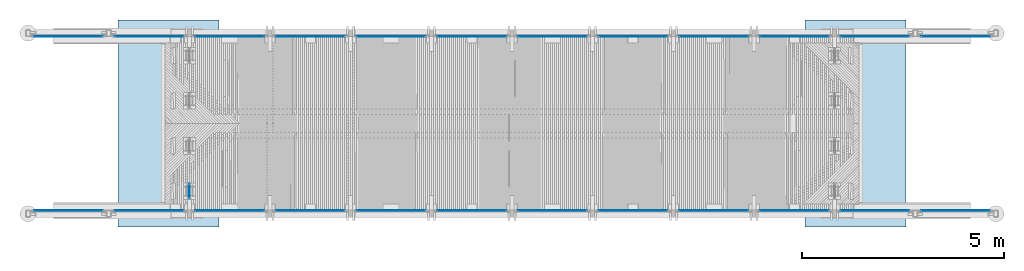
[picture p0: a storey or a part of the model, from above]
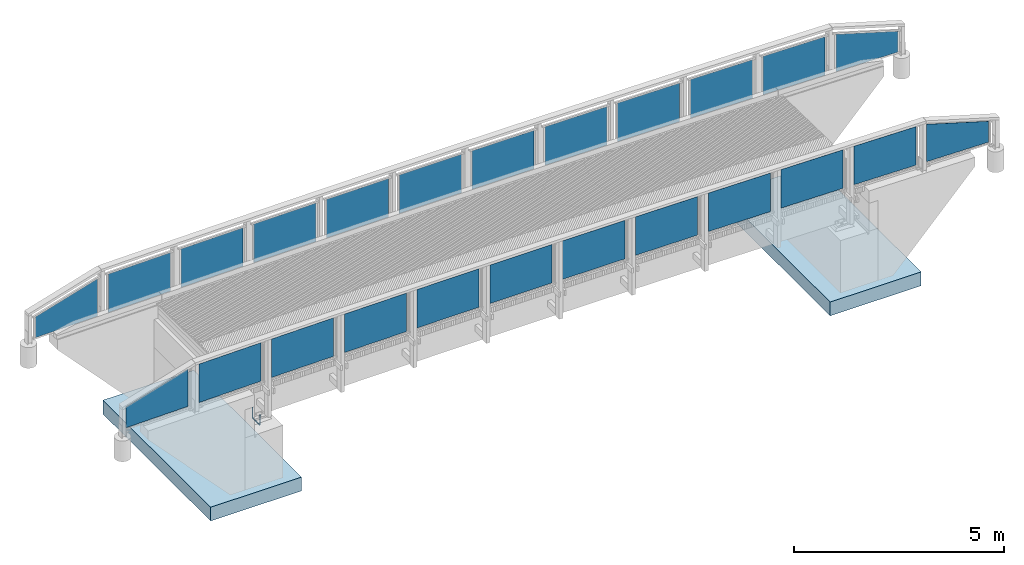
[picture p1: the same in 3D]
Properties of the parts of a building model (IFC2X3), part 2 of 2

# IfcBeam: 50*50 (546)
Name | Bottom elevation | Top elevation | Weight (kg) | Area per tons (m2) | Net surface area (m2) | Height (mm) | Tekla Quantity, Length (mm) | BaseQuantities, Length (mm) | OuterSurfaceArea (m2) | NetVolume (m3) | NetWeight (kg)
BEAM | +3.146 | +3.252 | 4.1 | 135.1 | 0.6 | 50 | 2880.8 | 2880.77 | 0.572949 | 0.0070735 | 4.2441
BEAM | +3.146 | +3.252 | 4.1 | 135.1 | 0.6 | 50 | 2880.8 | 2880.76 | 0.572941 | 0.00707335 | 4.24401
BEAM | +3.146 | +3.251 | 4.1 | 135.1 | 0.6 | 50 | 2880.8 | 2880.77 | 0.572949 | 0.0070735 | 4.2441
BEAM | +3.146 | +3.251 | 4.1 | 135.1 | 0.6 | 50 | 2880.8 | 2880.76 | 0.572941 | 0.00707335 | 4.24401
BEAM | +3.145 | +3.251 | 4.1 | 135.1 | 0.6 | 50 | 2880.8 | 2880.77 | 0.572949 | 0.0070735 | 4.2441
BEAM | +3.145 | +3.251 | 4.1 | 135.1 | 0.6 | 50 | 2880.8 | 2880.76 | 0.572941 | 0.00707335 | 4.24401
BEAM | +3.144 | +3.251 | 4.1 | 135.1 | 0.6 | 50 | 2880.8 | 2880.77 | 0.572949 | 0.0070735 | 4.2441
BEAM | +3.144 | +3.251 | 4.1 | 135.1 | 0.6 | 50 | 2880.8 | 2880.76 | 0.572941 | 0.00707335 | 4.24401
BEAM | +3.144 | +3.250 | 4.1 | 135.1 | 0.6 | 50 | 2880.8 | 2880.77 | 0.572949 | 0.0070735 | 4.2441
BEAM | +3.144 | +3.250 | 4.1 | 135.1 | 0.6 | 50 | 2880.8 | 2880.76 | 0.572941 | 0.00707335 | 4.24401
BEAM | +3.143 | +3.250 | 4.1 | 135.1 | 0.6 | 50 | 2880.8 | 2880.77 | 0.572949 | 0.0070735 | 4.2441
BEAM | +3.143 | +3.250 | 4.1 | 135.1 | 0.6 | 50 | 2880.8 | 2880.76 | 0.572941 | 0.00707335 | 4.24401
2 x BEAM | +3.142 | +3.249 | 4.1 | 135.1 | 0.6 | 50 | 2880.8 | 2880.77 | 0.572949 | 0.0070735 | 4.2441
2 x BEAM | +3.142 | +3.249 | 4.1 | 135.1 | 0.6 | 50 | 2880.8 | 2880.76 | 0.572941 | 0.00707335 | 4.24401
BEAM | +3.141 | +3.248 | 4.1 | 135.1 | 0.6 | 50 | 2880.8 | 2880.77 | 0.572949 | 0.0070735 | 4.2441
BEAM | +3.141 | +3.248 | 4.1 | 135.1 | 0.6 | 50 | 2880.8 | 2880.76 | 0.572941 | 0.00707335 | 4.24401
BEAM | +3.140 | +3.248 | 4.1 | 135.1 | 0.6 | 50 | 2880.8 | 2880.77 | 0.572949 | 0.0070735 | 4.2441
BEAM | +3.140 | +3.248 | 4.1 | 135.1 | 0.6 | 50 | 2880.8 | 2880.76 | 0.572941 | 0.00707335 | 4.24401
BEAM | +3.140 | +3.247 | 4.1 | 135.1 | 0.6 | 50 | 2880.8 | 2880.77 | 0.572949 | 0.0070735 | 4.2441
BEAM | +3.140 | +3.247 | 4.1 | 135.1 | 0.6 | 50 | 2880.8 | 2880.76 | 0.572941 | 0.00707335 | 4.24401
BEAM | +3.139 | +3.247 | 4.1 | 135.1 | 0.6 | 50 | 2880.8 | 2880.77 | 0.572949 | 0.0070735 | 4.2441
BEAM | +3.139 | +3.247 | 4.1 | 135.1 | 0.6 | 50 | 2880.8 | 2880.76 | 0.572941 | 0.00707335 | 4.24401
BEAM | +3.138 | +3.246 | 4.1 | 135.1 | 0.6 | 50 | 2880.8 | 2880.77 | 0.572949 | 0.0070735 | 4.2441
BEAM | +3.138 | +3.246 | 4.1 | 135.1 | 0.6 | 50 | 2880.8 | 2880.76 | 0.572941 | 0.00707335 | 4.24401
BEAM | +3.137 | +3.246 | 4.1 | 135.1 | 0.6 | 50 | 2880.8 | 2880.77 | 0.572949 | 0.0070735 | 4.2441
BEAM | +3.137 | +3.246 | 4.1 | 135.1 | 0.6 | 50 | 2880.8 | 2880.76 | 0.572941 | 0.00707335 | 4.24401
BEAM | +3.137 | +3.245 | 4.1 | 135.1 | 0.6 | 50 | 2880.8 | 2880.77 | 0.572949 | 0.0070735 | 4.2441
BEAM | +3.137 | +3.245 | 4.1 | 135.1 | 0.6 | 50 | 2880.8 | 2880.76 | 0.572941 | 0.00707335 | 4.24401
BEAM | +3.136 | +3.245 | 4.1 | 135.1 | 0.6 | 50 | 2880.8 | 2880.77 | 0.572949 | 0.0070735 | 4.2441
BEAM | +3.136 | +3.245 | 4.1 | 135.1 | 0.6 | 50 | 2880.8 | 2880.76 | 0.572941 | 0.00707335 | 4.24401
BEAM | +3.135 | +3.244 | 4.1 | 135.1 | 0.6 | 50 | 2880.8 | 2880.77 | 0.572949 | 0.0070735 | 4.2441
BEAM | +3.135 | +3.244 | 4.1 | 135.1 | 0.6 | 50 | 2880.8 | 2880.76 | 0.572941 | 0.00707335 | 4.24401
BEAM | +3.134 | +3.244 | 4.1 | 135.1 | 0.6 | 50 | 2880.8 | 2880.77 | 0.572949 | 0.0070735 | 4.2441
BEAM | +3.134 | +3.244 | 4.1 | 135.1 | 0.6 | 50 | 2880.8 | 2880.76 | 0.572941 | 0.00707335 | 4.24401
BEAM | +3.134 | +3.243 | 4.1 | 135.1 | 0.6 | 50 | 2880.8 | 2880.77 | 0.572949 | 0.0070735 | 4.2441
BEAM | +3.134 | +3.243 | 4.1 | 135.1 | 0.6 | 50 | 2880.8 | 2880.76 | 0.572941 | 0.00707335 | 4.24401
BEAM | +3.133 | +3.243 | 4.1 | 135.1 | 0.6 | 50 | 2880.8 | 2880.77 | 0.572949 | 0.0070735 | 4.2441
BEAM | +3.133 | +3.243 | 4.1 | 135.1 | 0.6 | 50 | 2880.8 | 2880.76 | 0.572941 | 0.00707335 | 4.24401
BEAM | +3.132 | +3.242 | 4.1 | 135.1 | 0.6 | 50 | 2880.8 | 2880.77 | 0.572949 | 0.0070735 | 4.2441
BEAM | +3.132 | +3.242 | 4.1 | 135.1 | 0.6 | 50 | 2880.8 | 2880.76 | 0.572941 | 0.00707335 | 4.24401
BEAM | +3.131 | +3.242 | 4.1 | 135.1 | 0.6 | 50 | 2880.8 | 2880.77 | 0.572949 | 0.0070735 | 4.2441
BEAM | +3.131 | +3.242 | 4.1 | 135.1 | 0.6 | 50 | 2880.8 | 2880.76 | 0.572941 | 0.00707335 | 4.24401
BEAM | +3.130 | +3.241 | 4.1 | 135.1 | 0.6 | 50 | 2880.8 | 2880.77 | 0.572949 | 0.0070735 | 4.2441
BEAM | +3.130 | +3.241 | 4.1 | 135.1 | 0.6 | 50 | 2880.8 | 2880.76 | 0.572941 | 0.00707335 | 4.24401
BEAM | +3.129 | +3.241 | 4.1 | 135.1 | 0.6 | 50 | 2880.8 | 2880.77 | 0.572949 | 0.0070735 | 4.2441
BEAM | +3.129 | +3.241 | 4.1 | 135.1 | 0.6 | 50 | 2880.8 | 2880.76 | 0.572941 | 0.00707335 | 4.24401
BEAM | +3.129 | +3.240 | 4.1 | 135.1 | 0.6 | 50 | 2880.8 | 2880.77 | 0.572949 | 0.0070735 | 4.2441
BEAM | +3.129 | +3.240 | 4.1 | 135.1 | 0.6 | 50 | 2880.8 | 2880.76 | 0.572941 | 0.00707335 | 4.24401
BEAM | +3.128 | +3.239 | 4.1 | 135.1 | 0.6 | 50 | 2880.8 | 2880.77 | 0.572949 | 0.0070735 | 4.2441
BEAM | +3.128 | +3.239 | 4.1 | 135.1 | 0.6 | 50 | 2880.8 | 2880.76 | 0.572941 | 0.00707335 | 4.24401
BEAM | +3.127 | +3.239 | 4.1 | 135.1 | 0.6 | 50 | 2880.8 | 2880.77 | 0.572949 | 0.0070735 | 4.2441
BEAM | +3.127 | +3.239 | 4.1 | 135.1 | 0.6 | 50 | 2880.8 | 2880.76 | 0.572941 | 0.00707335 | 4.24401
BEAM | +3.126 | +3.238 | 4.1 | 135.1 | 0.6 | 50 | 2880.8 | 2880.77 | 0.572949 | 0.0070735 | 4.2441
BEAM | +3.126 | +3.238 | 4.1 | 135.1 | 0.6 | 50 | 2880.8 | 2880.76 | 0.572941 | 0.00707335 | 4.24401
BEAM | +3.125 | +3.237 | 4.1 | 135.1 | 0.6 | 50 | 2880.8 | 2880.77 | 0.572949 | 0.0070735 | 4.2441
BEAM | +3.125 | +3.237 | 4.1 | 135.1 | 0.6 | 50 | 2880.8 | 2880.76 | 0.572941 | 0.00707335 | 4.24401
BEAM | +3.124 | +3.237 | 4.1 | 135.1 | 0.6 | 50 | 2880.8 | 2880.77 | 0.572949 | 0.0070735 | 4.2441
BEAM | +3.124 | +3.237 | 4.1 | 135.1 | 0.6 | 50 | 2880.8 | 2880.76 | 0.572941 | 0.00707335 | 4.24401

# IfcBeam: 810*250 (2)
In: Undefined
Description: 810*250; Material: CONCRETE/Concrete_Undefined
Pset_BeamCommon - LoadBearing: yes; Reference: Concrete_LP-1001/0(?)
Tekla Common - Bottom elevation: +1.924; Top elevation: +2.734; Phase: 100; Class: 1009
Tekla Quantity - Weight: 2298.8 kg; Volume: 1 m3; Gross footprint area: 1.2 m2; Area per tons: 4.5 m2; Net surface area: 10.4 m2; Height: 810 mm; Width: 250 mm; Length: 4730 mm
BaseQuantities - Length: 4730 mm; OuterSurfaceArea: 10.4326 m2; NetVolume: 0.957825 m3; NetWeight: 2298.78 kg

# IfcBeam: 945*140 (9)
In: Undefined
Description: 945*140; Material: TIMBER/Timber_Undefined
Tekla Common - Phase: 600; Class: 4011
Tekla Quantity - Weight: 71.8 kg; Volume: 0.1 m3; Gross footprint area: 0.1 m2; Area per tons: 31 m2; Net surface area: 2.2 m2; Height: 945 mm; Width: 140 mm; Length: 905 mm
Pset_BeamCommon - LoadBearing: yes; Reference: PP/0(?)
BaseQuantities - Length: 905 mm; OuterSurfaceArea: 2.22845 m2; NetVolume: 0.119732 m3; NetWeight: 71.8389 kg
Name | Bottom elevation | Top elevation
2 x PALKKI | +2.030 | +2.975
4 x PALKKI | +2.028 | +2.973
3 x PALKKI | +2.070 | +3.015

# IfcBeam: 990*215 (4)
In: Undefined
Description: 990*215; Material: TIMBER/Timber_Undefined
Pset_BeamCommon - LoadBearing: yes; Reference: PP/0(?)
Tekla Common - Phase: 400; Class: 4011
Tekla Quantity - Weight: 2137.4 kg; Volume: 3.6 m3; Gross footprint area: 0.1 m2; Area per tons: 19.1 m2; Net surface area: 40.8 m2; Height: 990 mm; Width: 215 mm; Length: 16892.3 mm
BaseQuantities - Length: 16892.3 mm; OuterSurfaceArea: 40.8264 m2; NetVolume: 3.5623 m3; NetWeight: 2137.38 kg
Name | Bottom elevation | Top elevation
2 x PALKKI | +1.985 | +3.025
2 x PALKKI | +2.007 | +3.047

# IfcBeam: L100*10 (16)
In: Undefined
Description: L100*10; Material: STEEL/S235JR
Pset_BeamCommon - LoadBearing: yes; Reference: P/0(?)
Tekla Common - Phase: 600; Class: 1
Tekla Quantity - Weight: 4.5 kg; Volume: 0 m3; Gross footprint area: 0 m2; Area per tons: 25.9 m2; Net surface area: 0.1 m2; Height: 100 mm; Width: 100 mm; Length: 300 mm
BaseQuantities - Length: 300 mm; OuterSurfaceArea: 0.117 m2; NetVolume: 0.00057 m3; NetWeight: 4.4745 kg
Name | Bottom elevation | Top elevation
8 x BEAM | +1.997 | +2.097
8 x BEAM | +1.975 | +2.075

# IfcBeam: L50*5 (72)
In: Undefined
Description: L50*5; Material: STEEL/S235JR
Pset_BeamCommon - LoadBearing: yes; Reference: P/0(?)
Tekla Quantity - Volume: 0 m3; Gross footprint area: 0 m2; Area per tons: 51.4 m2; Height: 50 mm; Width: 50 mm
Tekla Common - Phase: 600; Class: 1
Name | Weight (kg) | Net surface area (m2) | Tekla Quantity, Length (mm) | Bottom elevation | Top elevation | BaseQuantities, Length (mm) | OuterSurfaceArea (m2) | NetVolume (m3) | NetWeight (kg)
2 x BEAM | 4.1 | 0.2 | 1100 | +3.235 | +4.335 | 1099.99 | 0.213398 | 0.000522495 | 4.10159
2 x BEAM | 7 | 0.5 | 1849.2 | +3.185 | +3.262 | 1849.21 | 0.358746 | 0.000878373 | 6.89522
2 x BEAM | 2.2 | 0.1 | 590.1 | +3.205 | +3.795 | 590.059 | 0.114472 | 0.000275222 | 2.16049
2 x BEAM | 6.8 | 0.5 | 1825.9 | +3.155 | +3.232 | 1825.95 | 0.354234 | 0.00086697 | 6.80571
2 x BEAM | 4.1 | 0.2 | 1100 | +3.265 | +4.365 | 1099.99 | 0.213398 | 0.000522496 | 4.10159
BEAM | 7 | 0.5 | 1849.2 | +3.214 | +3.286 | 1849.13 | 0.358731 | 0.000878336 | 6.89494
2 x BEAM | 7 | 0.5 | 1849.2 | +4.335 | +4.412 | 1849.21 | 0.358746 | 0.000878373 | 6.89522
2 x BEAM | 4.1 | 0.2 | 1081.4 | +3.232 | +4.313 | 1081.36 | 0.209784 | 0.000511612 | 4.01615
2 x BEAM | 4.1 | 0.2 | 1100 | +3.262 | +4.362 | 1099.99 | 0.213398 | 0.000522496 | 4.10159
2 x BEAM | 4.1 | 0.2 | 1100 | +3.285 | +4.385 | 1099.99 | 0.213398 | 0.000522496 | 4.10159
2 x BEAM | 4.1 | 0.2 | 1100 | +3.302 | +4.402 | 1100 | 0.2134 | 0.000522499 | 4.10162
2 x BEAM | 4.1 | 0.2 | 1100 | +3.313 | +4.413 | 1100 | 0.2134 | 0.0005225 | 4.10162
2 x BEAM | 4.1 | 0.2 | 1100 | +3.316 | +4.416 | 1100 | 0.2134 | 0.0005225 | 4.10163
2 x BEAM | 4.1 | 0.2 | 1100 | +3.313 | +4.413 | 1100 | 0.2134 | 0.0005225 | 4.10163
2 x BEAM | 4.1 | 0.2 | 1100 | +3.304 | +4.404 | 1100 | 0.2134 | 0.0005225 | 4.10162
2 x BEAM | 4.1 | 0.2 | 1100 | +3.287 | +4.387 | 1100 | 0.2134 | 0.000522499 | 4.10162
BEAM | 7.3 | 0.5 | 1945.6 | +3.773 | +4.377 | 1945.6 | 0.377447 | 0.000917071 | 7.19901
BEAM | 7 | 0.5 | 1849.2 | +3.214 | +3.286 | 1849.12 | 0.35873 | 0.000878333 | 6.89491
BEAM | 7 | 0.5 | 1849.2 | +3.237 | +3.302 | 1849.06 | 0.358717 | 0.000878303 | 6.89468
BEAM | 7 | 0.5 | 1849 | +3.253 | +3.313 | 1849.02 | 0.358709 | 0.000878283 | 6.89452
BEAM | 7 | 0.5 | 1849 | +3.263 | +3.316 | 1849 | 0.358705 | 0.000878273 | 6.89445
BEAM | 7 | 0.5 | 1849 | +3.263 | +3.316 | 1849 | 0.358707 | 0.000878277 | 6.89447
BEAM | 7 | 0.5 | 1849 | +3.254 | +3.313 | 1849.02 | 0.358709 | 0.000878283 | 6.89452
BEAM | 7 | 0.5 | 1849.2 | +3.237 | +3.303 | 1849.07 | 0.358719 | 0.000878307 | 6.89471
BEAM | 7.3 | 0.5 | 1945.6 | +3.773 | +4.377 | 1945.6 | 0.377446 | 0.000917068 | 7.19899
BEAM | 7 | 0.5 | 1849.2 | +4.364 | +4.436 | 1849.12 | 0.35873 | 0.000878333 | 6.89491
BEAM | 7 | 0.5 | 1849.2 | +4.387 | +4.452 | 1849.06 | 0.358717 | 0.000878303 | 6.89468
BEAM | 7 | 0.5 | 1849 | +4.403 | +4.463 | 1849.02 | 0.358709 | 0.000878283 | 6.89452
BEAM | 7 | 0.5 | 1849 | +4.413 | +4.466 | 1849 | 0.358705 | 0.000878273 | 6.89445
BEAM | 7 | 0.5 | 1849 | +4.413 | +4.466 | 1849 | 0.358707 | 0.000878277 | 6.89447
BEAM | 7 | 0.5 | 1849 | +4.404 | +4.463 | 1849.02 | 0.358709 | 0.000878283 | 6.89452
BEAM | 7 | 0.5 | 1849.2 | +4.387 | +4.453 | 1849.07 | 0.358719 | 0.000878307 | 6.89471
BEAM | 7 | 0.5 | 1849.2 | +4.364 | +4.436 | 1849.13 | 0.358731 | 0.000878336 | 6.89494
2 x BEAM | 7 | 0.3 | 1849.2 | +3.185 | +3.262 | 1849.21 | 0.358746 | 0.000878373 | 6.89522
2 x BEAM | 7 | 0.3 | 1849.2 | +4.335 | +4.412 | 1849.21 | 0.358746 | 0.000878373 | 6.89522
BEAM | 7.3 | 0.3 | 1945.6 | +3.773 | +4.377 | 1945.6 | 0.377447 | 0.000917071 | 7.19901
2 x BEAM | 6.8 | 0.3 | 1825.9 | +3.155 | +3.232 | 1825.95 | 0.354234 | 0.00086697 | 6.80571
BEAM | 7 | 0.3 | 1849.2 | +3.214 | +3.286 | 1849.12 | 0.35873 | 0.000878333 | 6.89491
BEAM | 7 | 0.3 | 1849.2 | +3.237 | +3.302 | 1849.06 | 0.358717 | 0.000878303 | 6.89468
BEAM | 7 | 0.3 | 1849 | +3.253 | +3.313 | 1849.02 | 0.358709 | 0.000878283 | 6.89452
BEAM | 7 | 0.3 | 1849 | +3.263 | +3.316 | 1849 | 0.358705 | 0.000878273 | 6.89445
BEAM | 7 | 0.3 | 1849 | +3.263 | +3.316 | 1849 | 0.358707 | 0.000878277 | 6.89447
BEAM | 7 | 0.3 | 1849 | +3.254 | +3.313 | 1849.02 | 0.358709 | 0.000878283 | 6.89452
BEAM | 7 | 0.3 | 1849.2 | +3.237 | +3.303 | 1849.07 | 0.358719 | 0.000878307 | 6.89471
BEAM | 7.3 | 0.3 | 1945.6 | +3.773 | +4.377 | 1945.6 | 0.377446 | 0.000917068 | 7.19899
BEAM | 7 | 0.3 | 1849.2 | +4.364 | +4.436 | 1849.12 | 0.35873 | 0.000878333 | 6.89491
BEAM | 7 | 0.3 | 1849.2 | +4.387 | +4.452 | 1849.06 | 0.358717 | 0.000878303 | 6.89468
BEAM | 7 | 0.3 | 1849 | +4.403 | +4.463 | 1849.02 | 0.358709 | 0.000878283 | 6.89452
BEAM | 7 | 0.3 | 1849 | +4.413 | +4.466 | 1849 | 0.358705 | 0.000878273 | 6.89445
BEAM | 7 | 0.3 | 1849 | +4.413 | +4.466 | 1849 | 0.358707 | 0.000878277 | 6.89447
BEAM | 7 | 0.3 | 1849 | +4.404 | +4.463 | 1849.02 | 0.358709 | 0.000878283 | 6.89452
BEAM | 7 | 0.3 | 1849.2 | +4.387 | +4.453 | 1849.07 | 0.358719 | 0.000878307 | 6.89471
BEAM | 7 | 0.3 | 1849.2 | +3.214 | +3.286 | 1849.13 | 0.358731 | 0.000878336 | 6.89494
BEAM | 7 | 0.3 | 1849.2 | +4.364 | +4.436 | 1849.13 | 0.358731 | 0.000878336 | 6.89494

# IfcBeam: PL100*10 (8)
In: Undefined
Description: PL100*10; Material: STEEL/AISI316
Pset_BeamCommon - LoadBearing: yes; Reference: KPL/0(?)
Tekla Common - Phase: 600; Class: 8013
Tekla Quantity - Weight: 1.1 kg; Volume: 0 m3; Gross footprint area: 0 m2; Area per tons: 29.8 m2; Net surface area: 0 m2; Height: 100 mm; Width: 10 mm; Length: 140 mm
BaseQuantities - Length: 140 mm; OuterSurfaceArea: 0.0328 m2; NetVolume: 0.00014 m3; NetWeight: 1.099 kg
Name | Bottom elevation | Top elevation
4 x KAIDEPYLVÄS | +3.085 | +3.095
4 x KAIDEPYLVÄS | +3.113 | +3.123

# IfcBeam: PL45*10 (84)
In: Undefined
Description: PL45*10; Material: STEEL/S235JR
Tekla Common - Phase: 600; Class: 1
Tekla Quantity - Weight: 0.2 kg; Volume: 0 m3; Gross footprint area: 0 m2; Area per tons: 36.8 m2; Net surface area: 0 m2; Height: 45 mm; Width: 10 mm; Length: 45 mm
Pset_BeamCommon - LoadBearing: yes; Reference: P/0(?)
BaseQuantities - Length: 45 mm; OuterSurfaceArea: 0.00585 m2; NetVolume: 0.00002025 m3
Name | Bottom elevation | Top elevation | NetWeight (kg)
4 x BEAM | +4.362 | +4.407 | 0.158963
2 x BEAM | +4.335 | +4.380 | 0.158962
2 x BEAM | +4.385 | +4.431 | 0.158962
4 x BEAM | +4.364 | +4.409 | 0.158962
2 x BEAM | +4.402 | +4.447 | 0.158963
2 x BEAM | +4.387 | +4.432 | 0.158963
2 x BEAM | +4.412 | +4.458 | 0.158963
2 x BEAM | +4.403 | +4.449 | 0.158963
2 x BEAM | +4.416 | +4.461 | 0.158962
4 x BEAM | +4.413 | +4.458 | 0.158963
2 x BEAM | +4.416 | +4.461 | 0.158963
2 x BEAM | +4.403 | +4.449 | 0.158962
2 x BEAM | +4.413 | +4.458 | 0.158962
2 x BEAM | +4.387 | +4.432 | 0.158962
2 x BEAM | +4.403 | +4.448 | 0.158962
4 x BEAM | +3.775 | +3.820 | 0.158963
4 x BEAM | +4.324 | +4.369 | 0.158963
2 x BEAM | +3.217 | +3.262 | 0.158962
2 x BEAM | +4.335 | +4.380 | 0.158963
4 x BEAM | +3.219 | +3.264 | 0.158962
2 x BEAM | +3.241 | +3.286 | 0.158963
2 x BEAM | +4.386 | +4.431 | 0.158962
2 x BEAM | +3.217 | +3.262 | 0.158963
2 x BEAM | +3.240 | +3.286 | 0.158962
2 x BEAM | +3.257 | +3.302 | 0.158962
2 x BEAM | +3.242 | +3.287 | 0.158963
2 x BEAM | +3.267 | +3.313 | 0.158963
4 x BEAM | +3.258 | +3.304 | 0.158963
4 x BEAM | +3.271 | +3.316 | 0.158962
2 x BEAM | +3.268 | +3.313 | 0.158962
4 x BEAM | +3.268 | +3.313 | 0.158963
2 x BEAM | +3.242 | +3.287 | 0.158962
2 x BEAM | +3.258 | +3.303 | 0.158963

# IfcBeam: PL60*10 (12)
In: Undefined
Description: PL60*10; Material: STEEL/AISI316
Tekla Common - Phase: 600; Class: 8013
Tekla Quantity - Weight: 0.5 kg; Volume: 0 m3; Gross footprint area: 0 m2; Area per tons: 31.9 m2; Net surface area: 0 m2; Height: 60 mm; Width: 10 mm; Length: 115 mm
Pset_BeamCommon - LoadBearing: yes; Reference: KPL/0(?)
BaseQuantities - Length: 115 mm; OuterSurfaceArea: 0.0173 m2; NetVolume: 0.000069 m3; NetWeight: 0.54165 kg
Name | Bottom elevation | Top elevation
4 x KAIDEPYLVÄS | +3.143 | +3.153
8 x KAIDEPYLVÄS | +3.171 | +3.181

# IfcColumn: 180*100 (26)
In: Undefined
Description: 180*100; Material: TIMBER/Timber_Undefined
Tekla Common - Phase: 600; Class: 8013
Tekla Quantity - Volume: 0 m3; Gross footprint area: 0 m2; Height: 180 mm; Width: 100 mm
Pset_ColumnCommon - LoadBearing: yes; Reference: KPP/0(?)
Name | Bottom elevation | Top elevation | Weight (kg) | Area per tons (m2) | Net surface area (m2) | Tekla Quantity, Length (mm) | BaseQuantities, Length (mm) | OuterSurfaceArea (m2) | NetVolume (m3) | NetWeight (kg)
4 x KAIDEPYLVÄS | +3.095 | +3.910 | 8.7 | 56.1 | 0.5 | 815.8 | 815.84 | 0.485338 | 0.0144181 | 8.65086
4 x KAIDEPYLVÄS | +3.123 | +4.481 | 14.7 | 54.3 | 0.8 | 1358.6 | 1358.59 | 0.796347 | 0.0244396 | 14.6638
4 x KAIDEPYLVÄS | +2.260 | +4.510 | 24.3 | 53.3 | 1.3 | 2250 | 2250 | 1.296 | 0.0405 | 24.3
4 x KAIDEPYLVÄS | +2.283 | +4.533 | 24.3 | 53.3 | 1.3 | 2250 | 2250 | 1.296 | 0.0405 | 24.3
4 x KAIDEPYLVÄS | +2.300 | +4.550 | 24.3 | 53.3 | 1.3 | 2250 | 2250 | 1.296 | 0.0405 | 24.3
4 x KAIDEPYLVÄS | +2.310 | +4.560 | 24.3 | 53.3 | 1.3 | 2250 | 2250 | 1.296 | 0.0405 | 24.3
2 x KAIDEPYLVÄS | +2.313 | +4.563 | 24.3 | 53.3 | 1.3 | 2250 | 2250 | 1.296 | 0.0405 | 24.3

# IfcColumn: 524*639 (4)
In: Undefined
Description: 524*639; Material: CONCRETE/Concrete_Undefined
Pset_ColumnCommon - LoadBearing: yes; Reference: Concrete_P-1/0(?)
Tekla Common - Bottom elevation: +1.912; Top elevation: +1.975; Phase: 600; Class: 320
Tekla Quantity - Weight: 36.8 kg; Volume: 0 m3; Gross footprint area: 0.2 m2; Area per tons: 19 m2; Net surface area: 0.6 m2; Height: 514.8 mm; Width: 639 mm; Length: 63.5 mm
BaseQuantities - Length: 63.5137 mm; OuterSurfaceArea: 0.69991 m2; NetVolume: 0.0153352 m3; NetWeight: 36.8044 kg

# IfcColumn: 570*685 (4)
In: Undefined
Description: 570*685; Material: CONCRETE/Concrete_Undefined
Pset_ColumnCommon - LoadBearing: yes; Reference: Concrete_P-1/0(?)
Tekla Common - Bottom elevation: +1.911; Top elevation: +1.997; Phase: 600; Class: 320
Tekla Quantity - Weight: 55.5 kg; Volume: 0 m3; Gross footprint area: 0.2 m2; Area per tons: 14.9 m2; Net surface area: 0.8 m2; Height: 559.7 mm; Width: 685 mm; Length: 86 mm
BaseQuantities - Length: 85.9822 mm; OuterSurfaceArea: 0.828549 m2; NetVolume: 0.0231346 m3; NetWeight: 55.523 kg

# IfcColumn: D33 (16)
In: Undefined
Description: D33; Material: STEEL/Steel_Undefined
Pset_ColumnCommon - LoadBearing: yes; Reference: P/0(?)
Tekla Common - Phase: 600; Class: 1
Tekla Quantity - Weight: 0.1 kg; Volume: 0 m3; Gross footprint area: 0 m2; Area per tons: 30.1 m2; Net surface area: 0 m2; Height: 33 mm; Width: 33 mm; Length: 18 mm
BaseQuantities - Length: 18 mm; OuterSurfaceArea: 0.00347836 m2; NetVolume: 0.0000147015 m3; NetWeight: 0.115407 kg
Name | Bottom elevation | Top elevation
8 x BEAM | +2.015 | +2.033
8 x BEAM | +1.993 | +2.011

# IfcColumn: D38 (16)
In: Undefined
Description: D38; Material: STEEL/Steel_Undefined
Pset_ColumnCommon - LoadBearing: yes; Reference: P/0(?)
Tekla Common - Phase: 600; Class: 1
Tekla Quantity - Weight: 0.1 kg; Volume: 0 m3; Gross footprint area: 0 m2; Area per tons: 45.7 m2; Net surface area: 0 m2; Height: 38 mm; Width: 38 mm; Length: 8 mm
BaseQuantities - Length: 8 mm; OuterSurfaceArea: 0.00311017 m2; NetVolume: 0.000008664 m3; NetWeight: 0.0680124 kg
Name | Bottom elevation | Top elevation
8 x BEAM | +2.007 | +2.015
8 x BEAM | +1.985 | +1.993

# IfcColumn: D400 (4)
In: Undefined
Description: D400; Material: CONCRETE/Concrete_Undefined
Tekla Common - Bottom elevation: +2.445; Top elevation: +3.045; Phase: 600; Class: 320
Tekla Quantity - Weight: 180 kg; Volume: 0.1 m3; Gross footprint area: 0.1 m2; Area per tons: 5.6 m2; Net surface area: 1 m2; Height: 400 mm; Width: 400 mm; Length: 600 mm
Pset_ColumnCommon - LoadBearing: yes; Reference: Concrete_P-1/0(?)
BaseQuantities - Length: 600 mm; OuterSurfaceArea: 1.00308 m2; NetVolume: 0.075016 m3; NetWeight: 180.038 kg

# IfcColumn: L50*5 (24)
In: Undefined
Description: L50*5; Material: STEEL/S235JR
Tekla Common - Phase: 600; Class: 1
Tekla Quantity - Volume: 0 m3; Gross footprint area: 0 m2; Area per tons: 51.4 m2; Height: 50 mm; Width: 50 mm
Pset_ColumnCommon - LoadBearing: yes; Reference: P/0(?)
Name | Bottom elevation | Top elevation | Weight (kg) | Net surface area (m2) | Tekla Quantity, Length (mm) | BaseQuantities, Length (mm) | OuterSurfaceArea (m2) | NetVolume (m3) | NetWeight (kg)
2 x BEAM | +3.262 | +4.362 | 4.1 | 0.2 | 1100 | 1099.99 | 0.213398 | 0.000522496 | 4.10159
2 x BEAM | +3.232 | +4.313 | 4.1 | 0.2 | 1081.4 | 1081.36 | 0.209784 | 0.000511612 | 4.01615
2 x BEAM | +3.285 | +4.385 | 4.1 | 0.2 | 1100 | 1099.99 | 0.213398 | 0.000522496 | 4.10159
2 x BEAM | +3.205 | +3.795 | 2.2 | 0.1 | 590.1 | 590.059 | 0.114472 | 0.000275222 | 2.16049
2 x BEAM | +3.235 | +4.335 | 4.1 | 0.2 | 1100 | 1099.99 | 0.213398 | 0.000522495 | 4.10159
2 x BEAM | +3.265 | +4.365 | 4.1 | 0.2 | 1100 | 1099.99 | 0.213398 | 0.000522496 | 4.10159
2 x BEAM | +3.287 | +4.387 | 4.1 | 0.2 | 1100 | 1100 | 0.2134 | 0.000522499 | 4.10162
2 x BEAM | +3.304 | +4.404 | 4.1 | 0.2 | 1100 | 1100 | 0.2134 | 0.0005225 | 4.10162
2 x BEAM | +3.313 | +4.413 | 4.1 | 0.2 | 1100 | 1100 | 0.2134 | 0.0005225 | 4.10163
2 x BEAM | +3.316 | +4.416 | 4.1 | 0.2 | 1100 | 1100 | 0.2134 | 0.0005225 | 4.10163
2 x BEAM | +3.313 | +4.413 | 4.1 | 0.2 | 1100 | 1100 | 0.2134 | 0.0005225 | 4.10162
2 x BEAM | +3.302 | +4.402 | 4.1 | 0.2 | 1100 | 1100 | 0.2134 | 0.000522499 | 4.10162

# IfcColumn: PL150*10 (16)
In: Undefined
Description: PL150*10; Material: STEEL/AISI316
Tekla Common - Phase: 600; Class: 8013
Tekla Quantity - Weight: 6.8 kg; Volume: 0 m3; Gross footprint area: 0 m2; Area per tons: 27.7 m2; Net surface area: 0.2 m2; Height: 150 mm; Width: 10 mm; Length: 620 mm
Pset_ColumnCommon - LoadBearing: yes; Reference: KPL/0(?)
BaseQuantities - Length: 620 mm; OuterSurfaceArea: 0.1889 m2; NetVolume: 0.0008675 m3; NetWeight: 6.80987 kg
Name | Bottom elevation | Top elevation
8 x KAIDEPYLVÄS | +2.795 | +3.415
8 x KAIDEPYLVÄS | +2.823 | +3.443

# IfcColumn: PL300*215 (8)
In: Undefined
Description: PL300*215; Material: MISCELLANEOUS/NEOPREENI
Pset_ColumnCommon - LoadBearing: yes; Reference: P/0(?)
Tekla Common - Phase: 600; Class: 7
Tekla Quantity - Weight: 1 kg; Volume: 0 m3; Gross footprint area: 0.1 m2; Area per tons: 154.3 m2; Net surface area: 0.1 m2; Height: 300 mm; Width: 215 mm; Length: 10 mm
BaseQuantities - Length: 10 mm; OuterSurfaceArea: 0.1393 m2; NetVolume: 0.000645 m3; NetWeight: 0.903 kg
Name | Bottom elevation | Top elevation
4 x COLUMN | +1.975 | +1.985
4 x COLUMN | +1.997 | +2.007

# IfcMechanicalFastener: Bolt assembly (24)
In: Undefined
NominalDiameter: 20 mm; Material: Undefined
Tekla Bolt - Washer diameter: 20 mm; Washer type: DIN125; Washer name: W20-DIN125; Nut type: DIN934; Nut name: M20-DIN934; Slotted hole y: 0 mm; Location: Site
Name | NominalLength (mm) = Bolt length (mm) | Washer count | Nut count | Slotted hole x (mm) | Bolt hole diameter (mm) | Bolt count | Bolt size (mm) | Bolt standard | Bolt Name
16 x Bolt assembly | 30 | 0 | 0 | 30 | 30 | 1 | 30 | DIN933 | M20*30
8 x Bolt assembly | 270 | 4 | 2 | 0 | 22 | 2 | 20 | DIN931 | M20*270

# IfcPlate: PL5*1044 (4)
In: Undefined
Description: PL5*1044; Material: STEEL/S235JR
Tekla Common - Bottom elevation: +3.195; Top elevation: +4.312; Phase: 600; Class: 99
Tekla Quantity - Weight: 56.8 kg; Volume: 0 m3; Gross footprint area: 0 m2; Area per tons: 51.4 m2; Net surface area: 2.9 m2; Height: 1044.3 mm; Width: 5 mm; Length: 1953.1 mm
Pset_PlateCommon - LoadBearing: yes; Reference: 0(?)
BaseQuantities - Width: 1044.31 mm; NetArea: 2.91991 m2; GrossArea: 2.03968 m2; CrossSectionArea: 0.000025 m2; NetVolume: 0.00723501 m3; GrossVolume: 0.00723501 m3

# IfcPlate: PL5*1120 (20)
In: Undefined
Description: PL5*1120; Material: STEEL/S235JR
Pset_PlateCommon - LoadBearing: yes; Reference: 0(?)
Tekla Common - Phase: 600; Class: 99
Tekla Quantity - Weight: 75 kg; Volume: 0 m3; Gross footprint area: 0 m2; Area per tons: 51.3 m2; Net surface area: 3.8 m2; Height: 1119.9 mm; Width: 5 mm
BaseQuantities - CrossSectionArea: 0.000025 m2
Name | Bottom elevation | Top elevation | Length (mm) | Width (mm) | NetArea (m2) | GrossArea (m2) | NetVolume (m3) = GrossVolume (m3)
2 x PLATE | +3.225 | +4.372 | 1722.7 | 1119.85 | 3.84743 | 1.92918 | 0.00954794
4 x PLATE | +3.255 | +4.395 | 1718.7 | 1119.91 | 3.84743 | 1.92482 | 0.00954795
2 x PLATE | +3.225 | +4.372 | 1722.7 | 1119.86 | 3.84743 | 1.92918 | 0.00954794
4 x PLATE | +3.277 | +4.412 | 1714.8 | 1119.96 | 3.84745 | 1.92048 | 0.009548
4 x PLATE | +3.294 | +4.423 | 1710.9 | 1119.98 | 3.84746 | 1.91613 | 0.00954802
4 x PLATE | +3.303 | +4.426 | 1707 | 1120 | 3.84746 | 1.91178 | 0.00954803

# IfcReinforcingBar (16)
In: Undefined
NominalDiameter: 23 mm; CrossSectionArea: 0 m2; Material: A500HW
Tekla Reinforcement - TD: 40 mm; r: 20 mm; c: 311 mm; b: 378 mm; a: 311 mm; Length: 920 mm; Total Weight: 2.3 kg; Weight: 2.3 kg; Cast unit mark: LP/0(?); Phase: 100; Total Number: 1; Grade: A500HW; Name: REBAR; Size: 20; Rebar Mark: 0(?); Shape: D

# IfcSlab: 400*2500 (2)
In: Undefined
Description: 400*2500; PredefinedType: FLOOR; Material: CONCRETE/Concrete_Undefined
Tekla Common - Bottom elevation: +0.000; Top elevation: +0.400; Phase: 100; Class: 1003
Tekla Quantity - Weight: 12312 kg; Volume: 5.1 m3; Gross footprint area: 12.8 m2; Area per tons: 2.6 m2; Net surface area: 31.8 m2; Height: 2500 mm; Width: 400 mm; Length: 5130 mm
Pset_SlabCommon - LoadBearing: yes; Reference: Concrete_PL-1/0(?)
BaseQuantities - Width: 400 mm; NetVolume: 5.13 m3; NetArea: 12.825 m2; NetWeight: 12312 kg
